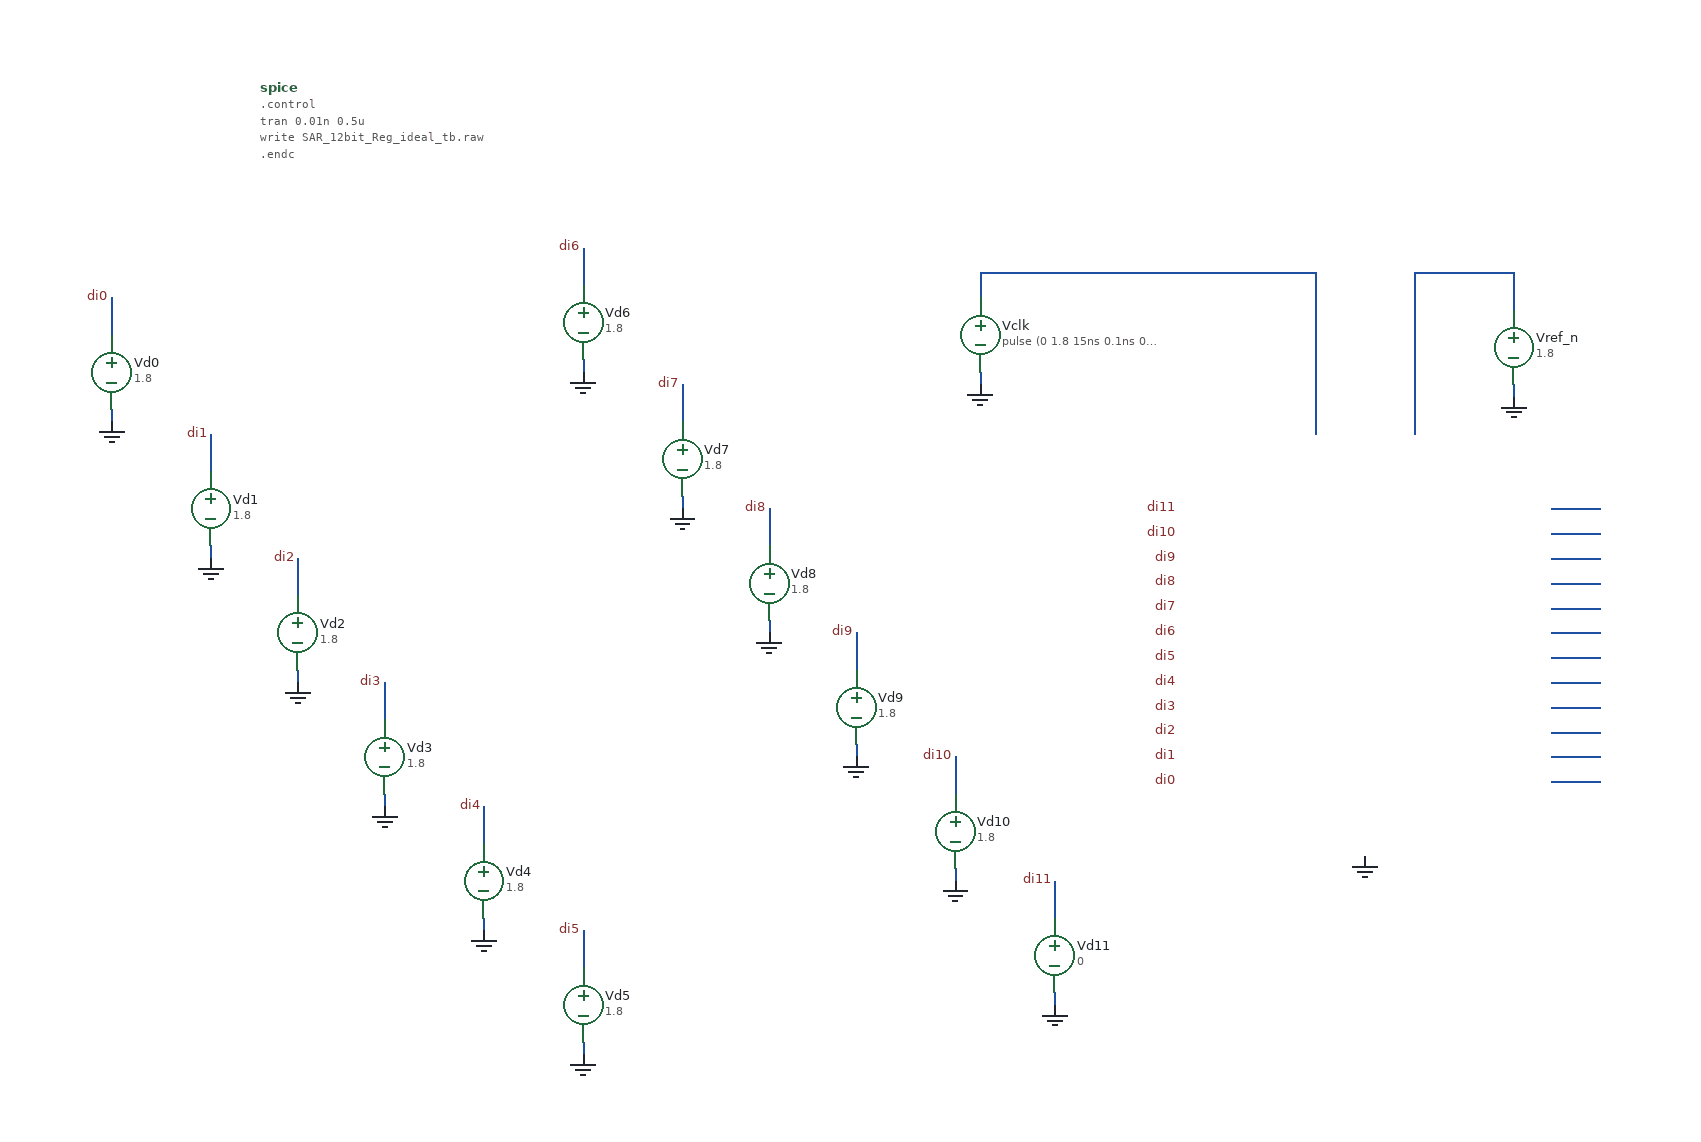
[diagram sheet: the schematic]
v {xschem version=3.4.6 file_version=1.2}
G {}
K {}
V {}
S {}
E {}
N -1020 -200 -1020 -190 {lab=GND}
N -1020 -290 -1020 -260 {lab=di0}
N -940 -90 -940 -80 {lab=GND}
N -940 -180 -940 -150 {lab=di1}
N -870 10 -870 20 {lab=GND}
N -870 -80 -870 -50 {lab=di2}
N -800 110 -800 120 {lab=GND}
N -800 20 -800 50 {lab=di3}
N -720 210 -720 220 {lab=GND}
N -720 120 -720 150 {lab=di4}
N -640 310 -640 320 {lab=GND}
N -640 220 -640 250 {lab=di5}
N -640 -240 -640 -230 {lab=GND}
N -640 -330 -640 -300 {lab=di6}
N -560 -130 -560 -120 {lab=GND}
N -560 -220 -560 -190 {lab=di7}
N -490 -30 -490 -20 {lab=GND}
N -490 -120 -490 -90 {lab=di8}
N -420 70 -420 80 {lab=GND}
N -420 -20 -420 10 {lab=di9}
N -340 170 -340 180 {lab=GND}
N -340 80 -340 110 {lab=di10}
N -260 270 -260 280 {lab=GND}
N -260 180 -260 210 {lab=di11}
N 110 -220 110 -210 {lab=GND}
N 110 -310 110 -280 {lab=#net1}
N 30 -310 30 -180 {lab=#net1}
N 30 -310 110 -310 {lab=#net1}
N 140 -120 180 -120 {lab=#net2}
N 140 -100 180 -100 {lab=#net3}
N 140 -80 180 -80 {lab=#net4}
N 140 -60 180 -60 {lab=#net5}
N 140 -40 180 -40 {lab=#net6}
N 140 -20 180 -20 {lab=#net7}
N 140 0 180 0 {lab=#net8}
N 140 20 180 20 {lab=#net9}
N 140 40 180 40 {lab=#net10}
N 140 60 180 60 {lab=#net11}
N 140 80 180 80 {lab=#net12}
N 140 100 180 100 {lab=#net13}
N -320 -230 -320 -220 {lab=GND}
N -320 -310 -320 -290 {lab=#net14}
N -320 -310 -50 -310 {lab=#net14}
N -50 -310 -50 -180 {lab=#net14}
C {devices/vsource.sym} -1020 -230 0 0 {name=Vd0 value=1.8 savecurrent=false}
C {devices/gnd.sym} -1020 -190 0 0 {name=l11 lab=GND}
C {devices/lab_pin.sym} -1020 -290 0 0 {name=p77 sig_type=std_logic lab=di0}
C {devices/vsource.sym} -940 -120 0 0 {name=Vd1 value=1.8 savecurrent=false}
C {devices/gnd.sym} -940 -80 0 0 {name=l10 lab=GND}
C {devices/lab_pin.sym} -940 -180 0 0 {name=p76 sig_type=std_logic lab=di1}
C {devices/vsource.sym} -870 -20 0 0 {name=Vd2 value=1.8 savecurrent=false}
C {devices/gnd.sym} -870 20 0 0 {name=l12 lab=GND}
C {devices/lab_pin.sym} -870 -80 0 0 {name=p78 sig_type=std_logic lab=di2}
C {devices/vsource.sym} -800 80 0 0 {name=Vd3 value=1.8 savecurrent=false}
C {devices/gnd.sym} -800 120 0 0 {name=l13 lab=GND}
C {devices/lab_pin.sym} -800 20 0 0 {name=p79 sig_type=std_logic lab=di3}
C {devices/vsource.sym} -720 180 0 0 {name=Vd4 value=1.8 savecurrent=false}
C {devices/gnd.sym} -720 220 0 0 {name=l14 lab=GND}
C {devices/lab_pin.sym} -720 120 0 0 {name=p80 sig_type=std_logic lab=di4}
C {devices/vsource.sym} -640 280 0 0 {name=Vd5 value=1.8 savecurrent=false}
C {devices/gnd.sym} -640 320 0 0 {name=l15 lab=GND}
C {devices/lab_pin.sym} -640 220 0 0 {name=p19 sig_type=std_logic lab=di5}
C {devices/vsource.sym} -640 -270 0 0 {name=Vd6 value=1.8 savecurrent=false}
C {devices/gnd.sym} -640 -230 0 0 {name=l16 lab=GND}
C {devices/lab_pin.sym} -640 -330 0 0 {name=p20 sig_type=std_logic lab=di6}
C {devices/vsource.sym} -560 -160 0 0 {name=Vd7 value=1.8 savecurrent=false}
C {devices/gnd.sym} -560 -120 0 0 {name=l17 lab=GND}
C {devices/lab_pin.sym} -560 -220 0 0 {name=p27 sig_type=std_logic lab=di7}
C {devices/vsource.sym} -490 -60 0 0 {name=Vd8 value=1.8 savecurrent=false}
C {devices/gnd.sym} -490 -20 0 0 {name=l18 lab=GND}
C {devices/lab_pin.sym} -490 -120 0 0 {name=p28 sig_type=std_logic lab=di8}
C {devices/vsource.sym} -420 40 0 0 {name=Vd9 value=1.8 savecurrent=false}
C {devices/gnd.sym} -420 80 0 0 {name=l19 lab=GND}
C {devices/lab_pin.sym} -420 -20 0 0 {name=p81 sig_type=std_logic lab=di9}
C {devices/vsource.sym} -340 140 0 0 {name=Vd10 value=1.8 savecurrent=false}
C {devices/gnd.sym} -340 180 0 0 {name=l20 lab=GND}
C {devices/lab_pin.sym} -340 80 0 0 {name=p82 sig_type=std_logic lab=di10}
C {devices/vsource.sym} -260 240 0 0 {name=Vd11 value=0 savecurrent=false}
C {devices/gnd.sym} -260 280 0 0 {name=l21 lab=GND}
C {devices/lab_pin.sym} -260 180 0 0 {name=p83 sig_type=std_logic lab=di11}
C {devices/code_shown.sym} -900 -460 0 0 {name=spice only_toplevel=false value="
.control
tran 0.01n 0.5u
write SAR_12bit_Reg_ideal_tb.raw
.endc
"}
C {devices/lab_pin.sym} -160 100 0 0 {name=p2 sig_type=std_logic lab=di0}
C {devices/lab_pin.sym} -160 80 0 0 {name=p3 sig_type=std_logic lab=di1}
C {devices/lab_pin.sym} -160 60 0 0 {name=p4 sig_type=std_logic lab=di2}
C {devices/lab_pin.sym} -160 40 0 0 {name=p5 sig_type=std_logic lab=di3}
C {devices/lab_pin.sym} -160 20 0 0 {name=p6 sig_type=std_logic lab=di4}
C {devices/lab_pin.sym} -160 0 0 0 {name=p7 sig_type=std_logic lab=di5}
C {devices/lab_pin.sym} -160 -20 0 0 {name=p8 sig_type=std_logic lab=di6}
C {devices/lab_pin.sym} -160 -40 0 0 {name=p9 sig_type=std_logic lab=di7}
C {devices/lab_pin.sym} -160 -60 0 0 {name=p10 sig_type=std_logic lab=di8}
C {devices/lab_pin.sym} -160 -80 0 0 {name=p11 sig_type=std_logic lab=di9}
C {devices/lab_pin.sym} -160 -100 0 0 {name=p12 sig_type=std_logic lab=di10}
C {devices/lab_pin.sym} -160 -120 0 0 {name=p13 sig_type=std_logic lab=di11}
C {devices/vsource.sym} 110 -250 0 0 {name=Vref_n value=1.8 savecurrent=false}
C {devices/gnd.sym} 110 -210 0 0 {name=l8 lab=GND}
C {devices/gnd.sym} -10 160 0 0 {name=l1 lab=GND}
C {devices/vsource.sym} -320 -260 0 0 {name=Vclk value="pulse (0 1.8 15ns 0.1ns 0.1ns 25ns 100ns)" savecurrent=false}
C {devices/gnd.sym} -320 -220 0 0 {name=l3 lab=GND}
C {project/verilogA_module/VerilogA_Register_12bit.sym} 0 -20 0 0 {name=X1 model=VerilogA_Register_12bit_cell spiceprefix=X}
